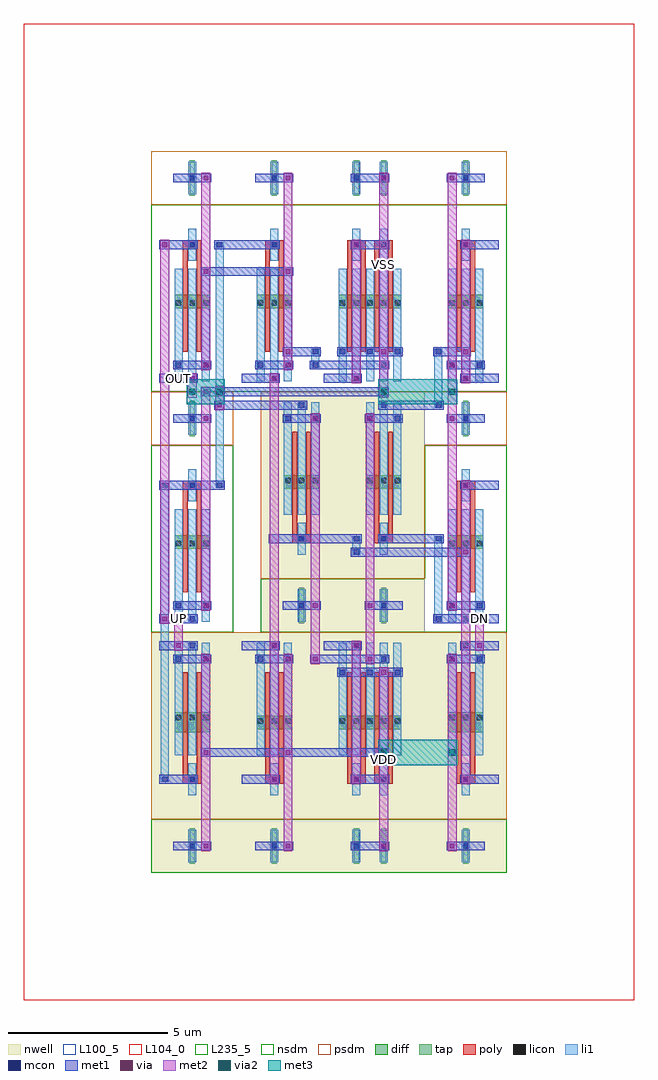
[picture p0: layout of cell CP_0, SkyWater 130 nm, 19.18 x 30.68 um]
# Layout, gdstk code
from math import pi, radians
import gdstk
lib = gdstk.Library(unit=1e-6, precision=1e-09)
def R(c, l, rs):  # rectangles x0, y0, x1, y1
    for r in rs: c.add(gdstk.rectangle(r[:2], r[2:], *l))
def A(c, l, x, y, w, h, nx, ny, dx, dy):  # array of equal rectangles
    R(c, l, [(x+i*dx, y+j*dy, x+i*dx+w, y+j*dy+h) for i in range(nx) for j in range(ny)])
def P(c, l, *ps):  # polygons
    for p in ps: c.add(gdstk.Polygon(p, *l))
nwell = (64, 20)
diff = (65, 20)
tap = (65, 44)
poly = (66, 20)
licon = (66, 44)
li1 = (67, 20)
mcon = (67, 44)
met1 = (68, 20)
via = (68, 44)
met2 = (69, 20)
via2 = (69, 44)
met3 = (70, 20)
nsdm = (93, 44)
psdm = (94, 20)
L100_5 = (100, 5)
L104_0 = (104, 0)
L235_5 = (235, 5)

scm_nmos_16357927_x1_y1_ = lib.new_cell('SCM_NMOS_16357927_X1_Y1_1670320497')
R(scm_nmos_16357927_x1_y1_, diff, [(0.735,2.625,2.705,3.045)])
R(scm_nmos_16357927_x1_y1_, tap, [(1.205,6.16,1.375,7.28), (2.065,6.16,2.235,7.28)])
A(scm_nmos_16357927_x1_y1_, poly, 1, 1.26, 0.15, 3.36, 4, 1, 0.43, 0)
R(scm_nmos_16357927_x1_y1_, poly, [(1,4.485,1.58,4.755), (1.86,4.485,2.44,4.755)])
A(scm_nmos_16357927_x1_y1_, licon, 0.775, 2.705, 0.17, 0.17, 3, 1, 0.43, 0)
A(scm_nmos_16357927_x1_y1_, licon, 1.635, 2.705, 0.17, 0.17, 3, 1, 0.43, 0)
R(scm_nmos_16357927_x1_y1_, licon, [(1.205,4.535,1.375,4.705), (2.065,4.535,2.235,4.705), (1.205,6.635,1.375,6.805), (2.065,6.635,2.235,6.805)])
A(scm_nmos_16357927_x1_y1_, li1, 0.735, 0.335, 0.25, 3.53, 5, 1, 0.43, 0)
R(scm_nmos_16357927_x1_y1_, li1, [(1.165,4.115,1.415,5.125), (2.025,4.115,2.275,5.125), (1.165,6.215,1.415,7.225), (2.025,6.215,2.275,7.225)])
A(scm_nmos_16357927_x1_y1_, mcon, 0.775, 1.175, 0.17, 0.17, 3, 1, 0.86, 0)
R(scm_nmos_16357927_x1_y1_, mcon, [(1.205,0.335,1.375,0.505), (2.065,0.755,2.235,0.925), (1.205,4.535,1.375,4.705), (2.065,4.535,2.235,4.705), (1.205,6.635,1.375,6.805), (2.065,6.635,2.235,6.805)])
R(scm_nmos_16357927_x1_y1_, met1, [(0.26,0.28,1.46,0.56), (1.12,0.7,2.32,0.98), (0.69,1.12,2.75,1.4), (1.12,4.48,2.32,4.76), (1.12,6.58,2.32,6.86)])
R(scm_nmos_16357927_x1_y1_, via, [(1.215,0.345,1.365,0.495), (2.075,1.185,2.225,1.335), (1.215,4.545,1.365,4.695), (2.075,6.645,2.225,6.795)])
R(scm_nmos_16357927_x1_y1_, met2, [(1.15,0.26,1.43,4.78), (2.01,1.1,2.29,6.88)])
R(scm_nmos_16357927_x1_y1_, nsdm, [(0,0,3.44,5.88)])
R(scm_nmos_16357927_x1_y1_, psdm, [(0,5.88,3.44,7.56)])
R(scm_nmos_16357927_x1_y1_, L100_5, [(0,0,3.44,7.56)])

scm_pmos_15963850_x1_y1_ = lib.new_cell('SCM_PMOS_15963850_X1_Y1_1670320498')
R(scm_pmos_15963850_x1_y1_, nwell, [(0,0,3.44,7.56)])
R(scm_pmos_15963850_x1_y1_, diff, [(0.735,2.625,2.705,3.045)])
R(scm_pmos_15963850_x1_y1_, tap, [(1.205,6.16,1.375,7.28), (2.065,6.16,2.235,7.28)])
A(scm_pmos_15963850_x1_y1_, poly, 1, 1.26, 0.15, 3.36, 4, 1, 0.43, 0)
R(scm_pmos_15963850_x1_y1_, poly, [(1,4.485,1.58,4.755), (1.86,4.485,2.44,4.755)])
A(scm_pmos_15963850_x1_y1_, licon, 0.775, 2.705, 0.17, 0.17, 3, 1, 0.43, 0)
A(scm_pmos_15963850_x1_y1_, licon, 1.635, 2.705, 0.17, 0.17, 3, 1, 0.43, 0)
R(scm_pmos_15963850_x1_y1_, licon, [(1.205,4.535,1.375,4.705), (2.065,4.535,2.235,4.705), (1.205,6.635,1.375,6.805), (2.065,6.635,2.235,6.805)])
A(scm_pmos_15963850_x1_y1_, li1, 0.735, 0.335, 0.25, 3.53, 5, 1, 0.43, 0)
R(scm_pmos_15963850_x1_y1_, li1, [(1.165,4.115,1.415,5.125), (2.025,4.115,2.275,5.125), (1.165,6.215,1.415,7.225), (2.025,6.215,2.275,7.225)])
A(scm_pmos_15963850_x1_y1_, mcon, 0.775, 1.175, 0.17, 0.17, 3, 1, 0.86, 0)
R(scm_pmos_15963850_x1_y1_, mcon, [(1.205,0.335,1.375,0.505), (2.065,0.755,2.235,0.925), (1.205,4.535,1.375,4.705), (2.065,4.535,2.235,4.705), (1.205,6.635,1.375,6.805), (2.065,6.635,2.235,6.805)])
R(scm_pmos_15963850_x1_y1_, met1, [(0.26,0.28,1.46,0.56), (1.12,0.7,2.32,0.98), (0.69,1.12,2.75,1.4), (1.12,4.48,2.32,4.76), (1.12,6.58,2.32,6.86)])
R(scm_pmos_15963850_x1_y1_, via, [(1.215,0.345,1.365,0.495), (2.075,1.185,2.225,1.335), (1.215,4.545,1.365,4.695), (2.075,6.645,2.225,6.795)])
R(scm_pmos_15963850_x1_y1_, met2, [(1.15,0.26,1.43,4.78), (2.01,1.1,2.29,6.88)])
R(scm_pmos_15963850_x1_y1_, nsdm, [(0,5.88,3.44,7.56)])
R(scm_pmos_15963850_x1_y1_, psdm, [(0,0,3.44,5.88)])
R(scm_pmos_15963850_x1_y1_, L100_5, [(0,0,3.44,7.56)])

nmos_s_96839798_x1_y1_16 = lib.new_cell('NMOS_S_96839798_X1_Y1_1670320484_1670320489')
R(nmos_s_96839798_x1_y1_16, diff, [(0.735,2.625,1.845,3.045)])
R(nmos_s_96839798_x1_y1_16, tap, [(1.205,6.16,1.375,7.28)])
R(nmos_s_96839798_x1_y1_16, poly, [(1,1.26,1.15,4.62), (1.43,1.26,1.58,4.62), (1,4.485,1.58,4.755)])
A(nmos_s_96839798_x1_y1_16, licon, 0.775, 2.705, 0.17, 0.17, 3, 1, 0.43, 0)
R(nmos_s_96839798_x1_y1_16, licon, [(1.205,4.535,1.375,4.705), (1.205,6.635,1.375,6.805)])
A(nmos_s_96839798_x1_y1_16, li1, 0.735, 0.335, 0.25, 3.53, 3, 1, 0.43, 0)
R(nmos_s_96839798_x1_y1_16, li1, [(1.165,4.115,1.415,5.125), (1.165,6.215,1.415,7.225)])
R(nmos_s_96839798_x1_y1_16, mcon, [(1.205,0.335,1.375,0.505), (0.775,0.755,0.945,0.925), (1.635,0.755,1.805,0.925), (1.205,4.535,1.375,4.705), (1.205,6.635,1.375,6.805)])
R(nmos_s_96839798_x1_y1_16, met1, [(0.26,0.28,1.46,0.56), (0.69,0.7,1.89,0.98), (0.26,4.48,1.46,4.76), (0.69,6.58,1.89,6.86)])
R(nmos_s_96839798_x1_y1_16, via, [(1.645,0.765,1.795,0.915), (1.645,6.645,1.795,6.795)])
R(nmos_s_96839798_x1_y1_16, met2, [(1.58,0.68,1.86,6.88)])
R(nmos_s_96839798_x1_y1_16, nsdm, [(0,0,2.58,5.88)])
R(nmos_s_96839798_x1_y1_16, psdm, [(0,5.88,2.58,7.56)])
R(nmos_s_96839798_x1_y1_16, L100_5, [(0,0,2.58,7.56)])

pmos_s_93230695_x1_y1_16 = lib.new_cell('PMOS_S_93230695_X1_Y1_1670320485_1670320489')
R(pmos_s_93230695_x1_y1_16, nwell, [(0,0,2.58,7.56)])
R(pmos_s_93230695_x1_y1_16, diff, [(0.735,2.52,1.845,3.15)])
R(pmos_s_93230695_x1_y1_16, tap, [(1.205,6.16,1.375,7.28)])
R(pmos_s_93230695_x1_y1_16, poly, [(1,1.26,1.15,4.62), (1.43,1.26,1.58,4.62), (1,4.485,1.58,4.755)])
A(pmos_s_93230695_x1_y1_16, licon, 0.775, 2.6, 0.17, 0.17, 3, 1, 0.43, 0)
R(pmos_s_93230695_x1_y1_16, licon, [(1.205,4.535,1.375,4.705), (1.205,6.635,1.375,6.805)])
A(pmos_s_93230695_x1_y1_16, li1, 0.735, 0.335, 0.25, 3.53, 3, 1, 0.43, 0)
R(pmos_s_93230695_x1_y1_16, li1, [(1.165,4.115,1.415,5.125), (1.165,6.215,1.415,7.225)])
R(pmos_s_93230695_x1_y1_16, mcon, [(1.205,0.335,1.375,0.505), (0.775,0.755,0.945,0.925), (1.635,0.755,1.805,0.925), (1.205,4.535,1.375,4.705), (1.205,6.635,1.375,6.805)])
R(pmos_s_93230695_x1_y1_16, met1, [(0.26,0.28,1.46,0.56), (0.69,0.7,1.89,0.98), (0.26,4.48,1.46,4.76), (0.69,6.58,1.89,6.86)])
R(pmos_s_93230695_x1_y1_16, via, [(1.645,0.765,1.795,0.915), (1.645,6.645,1.795,6.795)])
R(pmos_s_93230695_x1_y1_16, met2, [(1.58,0.68,1.86,6.88)])
R(pmos_s_93230695_x1_y1_16, nsdm, [(0,5.88,2.58,7.56)])
R(pmos_s_93230695_x1_y1_16, psdm, [(0,0,2.58,5.88)])
R(pmos_s_93230695_x1_y1_16, L100_5, [(0,0,2.58,7.56)])

inv_92586643_0_0_1670320 = lib.new_cell('INV_92586643_0_0_1670320489')
R(inv_92586643_0_0_1670320, li1, [(2.025,2.855,2.275,3.025), (2.025,2.855,2.275,3.025), (2.025,2.94,2.275,12.18), (2.025,12.095,2.275,12.265), (2.025,12.095,2.275,12.265)])
R(inv_92586643_0_0_1670320, mcon, [(2.065,2.855,2.235,3.025), (2.065,2.855,2.235,3.025), (2.065,12.095,2.235,12.265), (2.065,12.095,2.235,12.265)])
R(inv_92586643_0_0_1670320, met1, [(1.98,2.8,2.32,3.08), (1.98,2.8,2.32,3.08), (1.56,7,1.88,7.28), (1.56,7,1.88,7.28), (1.56,7.84,1.88,8.12), (1.56,7.84,1.88,8.12), (1.98,12.04,2.32,12.32), (1.98,12.04,2.32,12.32)])
P(inv_92586643_0_0_1670320, met1, [(0,0),(0,0),(0,0),(0,0)],
  [(0,0),(0,0),(0,0),(0,0)],
  [(0,0),(0,0),(0,0),(0,0)],
  [(0,0),(0,0),(0,0),(0,0)])
R(inv_92586643_0_0_1670320, via, [(1.645,7.065,1.795,7.215), (1.645,7.065,1.795,7.215), (1.645,7.905,1.795,8.055), (1.645,7.905,1.795,8.055)])
R(inv_92586643_0_0_1670320, met2, [(1.58,6.98,1.86,7.3), (1.58,6.98,1.86,7.3), (1.58,7.14,1.86,7.98), (1.58,7.82,1.86,8.14), (1.58,7.82,1.86,8.14)])
P(inv_92586643_0_0_1670320, met2, [(0,0),(0,0),(0,0),(0,0)],
  [(0,0),(0,0),(0,0),(0,0)])
R(inv_92586643_0_0_1670320, L235_5, [(0,0,2.58,15.12)])
inv_92586643_0_0_1670320.add(gdstk.Reference(nmos_s_96839798_x1_y1_16, (2.58,7.56), rotation=pi))
inv_92586643_0_0_1670320.add(gdstk.Reference(pmos_s_93230695_x1_y1_16, (2.58,7.56), rotation=pi, x_reflection=True))

c_nmos_s_96839798_x1_y1_16 = lib.new_cell('NMOS_S_96839798_X1_Y1_1670320484_1670320490')
R(c_nmos_s_96839798_x1_y1_16, diff, [(0.735,2.625,1.845,3.045)])
R(c_nmos_s_96839798_x1_y1_16, tap, [(1.205,6.16,1.375,7.28)])
R(c_nmos_s_96839798_x1_y1_16, poly, [(1,1.26,1.15,4.62), (1.43,1.26,1.58,4.62), (1,4.485,1.58,4.755)])
A(c_nmos_s_96839798_x1_y1_16, licon, 0.775, 2.705, 0.17, 0.17, 3, 1, 0.43, 0)
R(c_nmos_s_96839798_x1_y1_16, licon, [(1.205,4.535,1.375,4.705), (1.205,6.635,1.375,6.805)])
A(c_nmos_s_96839798_x1_y1_16, li1, 0.735, 0.335, 0.25, 3.53, 3, 1, 0.43, 0)
R(c_nmos_s_96839798_x1_y1_16, li1, [(1.165,4.115,1.415,5.125), (1.165,6.215,1.415,7.225)])
R(c_nmos_s_96839798_x1_y1_16, mcon, [(1.205,0.335,1.375,0.505), (0.775,0.755,0.945,0.925), (1.635,0.755,1.805,0.925), (1.205,4.535,1.375,4.705), (1.205,6.635,1.375,6.805)])
R(c_nmos_s_96839798_x1_y1_16, met1, [(0.26,0.28,1.46,0.56), (0.69,0.7,1.89,0.98), (0.26,4.48,1.46,4.76), (0.69,6.58,1.89,6.86)])
R(c_nmos_s_96839798_x1_y1_16, via, [(1.645,0.765,1.795,0.915), (1.645,6.645,1.795,6.795)])
R(c_nmos_s_96839798_x1_y1_16, met2, [(1.58,0.68,1.86,6.88)])
R(c_nmos_s_96839798_x1_y1_16, nsdm, [(0,0,2.58,5.88)])
R(c_nmos_s_96839798_x1_y1_16, psdm, [(0,5.88,2.58,7.56)])
R(c_nmos_s_96839798_x1_y1_16, L100_5, [(0,0,2.58,7.56)])

c_pmos_s_93230695_x1_y1_16 = lib.new_cell('PMOS_S_93230695_X1_Y1_1670320485_1670320490')
R(c_pmos_s_93230695_x1_y1_16, nwell, [(0,0,2.58,7.56)])
R(c_pmos_s_93230695_x1_y1_16, diff, [(0.735,2.52,1.845,3.15)])
R(c_pmos_s_93230695_x1_y1_16, tap, [(1.205,6.16,1.375,7.28)])
R(c_pmos_s_93230695_x1_y1_16, poly, [(1,1.26,1.15,4.62), (1.43,1.26,1.58,4.62), (1,4.485,1.58,4.755)])
A(c_pmos_s_93230695_x1_y1_16, licon, 0.775, 2.6, 0.17, 0.17, 3, 1, 0.43, 0)
R(c_pmos_s_93230695_x1_y1_16, licon, [(1.205,4.535,1.375,4.705), (1.205,6.635,1.375,6.805)])
A(c_pmos_s_93230695_x1_y1_16, li1, 0.735, 0.335, 0.25, 3.53, 3, 1, 0.43, 0)
R(c_pmos_s_93230695_x1_y1_16, li1, [(1.165,4.115,1.415,5.125), (1.165,6.215,1.415,7.225)])
R(c_pmos_s_93230695_x1_y1_16, mcon, [(1.205,0.335,1.375,0.505), (0.775,0.755,0.945,0.925), (1.635,0.755,1.805,0.925), (1.205,4.535,1.375,4.705), (1.205,6.635,1.375,6.805)])
R(c_pmos_s_93230695_x1_y1_16, met1, [(0.26,0.28,1.46,0.56), (0.69,0.7,1.89,0.98), (0.26,4.48,1.46,4.76), (0.69,6.58,1.89,6.86)])
R(c_pmos_s_93230695_x1_y1_16, via, [(1.645,0.765,1.795,0.915), (1.645,6.645,1.795,6.795)])
R(c_pmos_s_93230695_x1_y1_16, met2, [(1.58,0.68,1.86,6.88)])
R(c_pmos_s_93230695_x1_y1_16, nsdm, [(0,5.88,2.58,7.56)])
R(c_pmos_s_93230695_x1_y1_16, psdm, [(0,0,2.58,5.88)])
R(c_pmos_s_93230695_x1_y1_16, L100_5, [(0,0,2.58,7.56)])

inv_92586643_1_0_1670320 = lib.new_cell('INV_92586643_1_0_1670320490')
R(inv_92586643_1_0_1670320, met1, [(1.13,2.8,1.45,3.08), (1.13,2.8,1.45,3.08), (1.56,7,1.88,7.28), (1.56,7,1.88,7.28), (1.56,7.84,1.88,8.12), (1.56,7.84,1.88,8.12), (1.13,12.04,1.45,12.32), (1.13,12.04,1.45,12.32)])
P(inv_92586643_1_0_1670320, met1, [(0,0),(0,0),(0,0),(0,0)],
  [(0,0),(0,0),(0,0),(0,0)],
  [(0,0),(0,0),(0,0),(0,0)],
  [(0,0),(0,0),(0,0),(0,0)])
R(inv_92586643_1_0_1670320, via, [(1.215,2.865,1.365,3.015), (1.215,2.865,1.365,3.015), (1.645,7.065,1.795,7.215), (1.645,7.065,1.795,7.215), (1.645,7.905,1.795,8.055), (1.645,7.905,1.795,8.055), (1.215,12.105,1.365,12.255), (1.215,12.105,1.365,12.255)])
R(inv_92586643_1_0_1670320, met2, [(1.15,2.78,1.43,3.1), (1.15,2.78,1.43,3.1), (1.15,2.94,1.43,12.18), (1.58,6.98,1.86,7.3), (1.58,6.98,1.86,7.3), (1.58,7.14,1.86,7.98), (1.58,7.82,1.86,8.14), (1.58,7.82,1.86,8.14), (1.15,12.02,1.43,12.34), (1.15,12.02,1.43,12.34)])
P(inv_92586643_1_0_1670320, met2, [(0,0),(0,0),(0,0),(0,0)],
  [(0,0),(0,0),(0,0),(0,0)])
R(inv_92586643_1_0_1670320, L235_5, [(0,0,2.58,15.12)])
inv_92586643_1_0_1670320.add(gdstk.Reference(c_nmos_s_96839798_x1_y1_16, (2.58,7.56), rotation=pi))
inv_92586643_1_0_1670320.add(gdstk.Reference(c_pmos_s_93230695_x1_y1_16, (2.58,7.56), rotation=pi, x_reflection=True))

dcl_nmos_s_62101695_x1_y = lib.new_cell('DCL_NMOS_S_62101695_X1_Y1_1670320491')
R(dcl_nmos_s_62101695_x1_y, diff, [(0.735,2.625,1.845,3.045)])
R(dcl_nmos_s_62101695_x1_y, tap, [(1.205,6.16,1.375,7.28)])
R(dcl_nmos_s_62101695_x1_y, poly, [(1,1.26,1.15,4.62), (1.43,1.26,1.58,4.62), (1,4.485,1.58,4.755)])
A(dcl_nmos_s_62101695_x1_y, licon, 0.775, 2.705, 0.17, 0.17, 3, 1, 0.43, 0)
R(dcl_nmos_s_62101695_x1_y, licon, [(1.205,4.535,1.375,4.705), (1.205,6.635,1.375,6.805)])
A(dcl_nmos_s_62101695_x1_y, li1, 0.735, 0.335, 0.25, 3.53, 3, 1, 0.43, 0)
R(dcl_nmos_s_62101695_x1_y, li1, [(1.165,4.115,1.415,5.125), (1.165,6.215,1.415,7.225)])
R(dcl_nmos_s_62101695_x1_y, mcon, [(1.205,0.335,1.375,0.505), (0.775,0.755,0.945,0.925), (1.635,0.755,1.805,0.925), (1.205,4.535,1.375,4.705), (1.205,6.635,1.375,6.805)])
R(dcl_nmos_s_62101695_x1_y, met1, [(0.26,0.28,1.46,0.56), (0.69,0.7,1.89,0.98), (0.26,4.48,1.46,4.76), (0.69,6.58,1.89,6.86)])
R(dcl_nmos_s_62101695_x1_y, via, [(1.215,0.345,1.365,0.495), (1.645,0.765,1.795,0.915), (1.215,4.545,1.365,4.695), (1.645,6.645,1.795,6.795)])
R(dcl_nmos_s_62101695_x1_y, met2, [(1.15,0.26,1.43,4.78), (1.58,0.68,1.86,6.88)])
R(dcl_nmos_s_62101695_x1_y, nsdm, [(0,0,2.58,5.88)])
R(dcl_nmos_s_62101695_x1_y, psdm, [(0,5.88,2.58,7.56)])
R(dcl_nmos_s_62101695_x1_y, L100_5, [(0,0,2.58,7.56)])

dcl_pmos_s_57934405_x1_y = lib.new_cell('DCL_PMOS_S_57934405_X1_Y1_1670320492')
R(dcl_pmos_s_57934405_x1_y, nwell, [(0,0,2.58,7.56)])
R(dcl_pmos_s_57934405_x1_y, diff, [(0.735,2.625,1.845,3.045)])
R(dcl_pmos_s_57934405_x1_y, tap, [(1.205,6.16,1.375,7.28)])
R(dcl_pmos_s_57934405_x1_y, poly, [(1,1.26,1.15,4.62), (1.43,1.26,1.58,4.62), (1,4.485,1.58,4.755)])
A(dcl_pmos_s_57934405_x1_y, licon, 0.775, 2.705, 0.17, 0.17, 3, 1, 0.43, 0)
R(dcl_pmos_s_57934405_x1_y, licon, [(1.205,4.535,1.375,4.705), (1.205,6.635,1.375,6.805)])
A(dcl_pmos_s_57934405_x1_y, li1, 0.735, 0.335, 0.25, 3.53, 3, 1, 0.43, 0)
R(dcl_pmos_s_57934405_x1_y, li1, [(1.165,4.115,1.415,5.125), (1.165,6.215,1.415,7.225)])
R(dcl_pmos_s_57934405_x1_y, mcon, [(1.205,0.335,1.375,0.505), (0.775,0.755,0.945,0.925), (1.635,0.755,1.805,0.925), (1.205,4.535,1.375,4.705), (1.205,6.635,1.375,6.805)])
R(dcl_pmos_s_57934405_x1_y, met1, [(0.26,0.28,1.46,0.56), (0.69,0.7,1.89,0.98), (0.26,4.48,1.46,4.76), (0.69,6.58,1.89,6.86)])
R(dcl_pmos_s_57934405_x1_y, via, [(1.215,0.345,1.365,0.495), (1.645,0.765,1.795,0.915), (1.215,4.545,1.365,4.695), (1.645,6.645,1.795,6.795)])
R(dcl_pmos_s_57934405_x1_y, met2, [(1.15,0.26,1.43,4.78), (1.58,0.68,1.86,6.88)])
R(dcl_pmos_s_57934405_x1_y, nsdm, [(0,5.88,2.58,7.56)])
R(dcl_pmos_s_57934405_x1_y, psdm, [(0,0,2.58,5.88)])
R(dcl_pmos_s_57934405_x1_y, L100_5, [(0,0,2.58,7.56)])

nmos_s_58782418_x1_y1_16 = lib.new_cell('NMOS_S_58782418_X1_Y1_1670320493')
R(nmos_s_58782418_x1_y1_16, diff, [(0.735,2.625,1.845,3.045)])
R(nmos_s_58782418_x1_y1_16, tap, [(1.205,6.16,1.375,7.28)])
R(nmos_s_58782418_x1_y1_16, poly, [(1,1.26,1.15,4.62), (1.43,1.26,1.58,4.62), (1,4.485,1.58,4.755)])
A(nmos_s_58782418_x1_y1_16, licon, 0.775, 2.705, 0.17, 0.17, 3, 1, 0.43, 0)
R(nmos_s_58782418_x1_y1_16, licon, [(1.205,4.535,1.375,4.705), (1.205,6.635,1.375,6.805)])
A(nmos_s_58782418_x1_y1_16, li1, 0.735, 0.335, 0.25, 3.53, 3, 1, 0.43, 0)
R(nmos_s_58782418_x1_y1_16, li1, [(1.165,4.115,1.415,5.125), (1.165,6.215,1.415,7.225)])
R(nmos_s_58782418_x1_y1_16, mcon, [(1.205,0.335,1.375,0.505), (0.775,0.755,0.945,0.925), (1.635,0.755,1.805,0.925), (1.205,4.535,1.375,4.705), (1.205,6.635,1.375,6.805)])
R(nmos_s_58782418_x1_y1_16, met1, [(0.26,0.28,1.46,0.56), (0.69,0.7,1.89,0.98), (0.26,4.48,1.46,4.76), (0.69,6.58,1.89,6.86)])
R(nmos_s_58782418_x1_y1_16, via, [(1.645,0.765,1.795,0.915), (1.645,6.645,1.795,6.795)])
R(nmos_s_58782418_x1_y1_16, met2, [(1.58,0.68,1.86,6.88)])
R(nmos_s_58782418_x1_y1_16, nsdm, [(0,0,2.58,5.88)])
R(nmos_s_58782418_x1_y1_16, psdm, [(0,5.88,2.58,7.56)])
R(nmos_s_58782418_x1_y1_16, L100_5, [(0,0,2.58,7.56)])

c_nmos_s_96839798_x1_y1_16_ = lib.new_cell('NMOS_S_96839798_X1_Y1_1670320494')
R(c_nmos_s_96839798_x1_y1_16_, diff, [(0.735,2.625,1.845,3.045)])
R(c_nmos_s_96839798_x1_y1_16_, tap, [(1.205,6.16,1.375,7.28)])
R(c_nmos_s_96839798_x1_y1_16_, poly, [(1,1.26,1.15,4.62), (1.43,1.26,1.58,4.62), (1,4.485,1.58,4.755)])
A(c_nmos_s_96839798_x1_y1_16_, licon, 0.775, 2.705, 0.17, 0.17, 3, 1, 0.43, 0)
R(c_nmos_s_96839798_x1_y1_16_, licon, [(1.205,4.535,1.375,4.705), (1.205,6.635,1.375,6.805)])
A(c_nmos_s_96839798_x1_y1_16_, li1, 0.735, 0.335, 0.25, 3.53, 3, 1, 0.43, 0)
R(c_nmos_s_96839798_x1_y1_16_, li1, [(1.165,4.115,1.415,5.125), (1.165,6.215,1.415,7.225)])
R(c_nmos_s_96839798_x1_y1_16_, mcon, [(1.205,0.335,1.375,0.505), (0.775,0.755,0.945,0.925), (1.635,0.755,1.805,0.925), (1.205,4.535,1.375,4.705), (1.205,6.635,1.375,6.805)])
R(c_nmos_s_96839798_x1_y1_16_, met1, [(0.26,0.28,1.46,0.56), (0.69,0.7,1.89,0.98), (0.26,4.48,1.46,4.76), (0.69,6.58,1.89,6.86)])
R(c_nmos_s_96839798_x1_y1_16_, via, [(1.645,0.765,1.795,0.915), (1.645,6.645,1.795,6.795)])
R(c_nmos_s_96839798_x1_y1_16_, met2, [(1.58,0.68,1.86,6.88)])
R(c_nmos_s_96839798_x1_y1_16_, nsdm, [(0,0,2.58,5.88)])
R(c_nmos_s_96839798_x1_y1_16_, psdm, [(0,5.88,2.58,7.56)])
R(c_nmos_s_96839798_x1_y1_16_, L100_5, [(0,0,2.58,7.56)])

pmos_s_48783884_x1_y1_16 = lib.new_cell('PMOS_S_48783884_X1_Y1_1670320495')
R(pmos_s_48783884_x1_y1_16, nwell, [(0,0,2.58,7.56)])
R(pmos_s_48783884_x1_y1_16, diff, [(0.735,2.625,1.845,3.045)])
R(pmos_s_48783884_x1_y1_16, tap, [(1.205,6.16,1.375,7.28)])
R(pmos_s_48783884_x1_y1_16, poly, [(1,1.26,1.15,4.62), (1.43,1.26,1.58,4.62), (1,4.485,1.58,4.755)])
A(pmos_s_48783884_x1_y1_16, licon, 0.775, 2.705, 0.17, 0.17, 3, 1, 0.43, 0)
R(pmos_s_48783884_x1_y1_16, licon, [(1.205,4.535,1.375,4.705), (1.205,6.635,1.375,6.805)])
A(pmos_s_48783884_x1_y1_16, li1, 0.735, 0.335, 0.25, 3.53, 3, 1, 0.43, 0)
R(pmos_s_48783884_x1_y1_16, li1, [(1.165,4.115,1.415,5.125), (1.165,6.215,1.415,7.225)])
R(pmos_s_48783884_x1_y1_16, mcon, [(1.205,0.335,1.375,0.505), (0.775,0.755,0.945,0.925), (1.635,0.755,1.805,0.925), (1.205,4.535,1.375,4.705), (1.205,6.635,1.375,6.805)])
R(pmos_s_48783884_x1_y1_16, met1, [(0.26,0.28,1.46,0.56), (0.69,0.7,1.89,0.98), (0.26,4.48,1.46,4.76), (0.69,6.58,1.89,6.86)])
R(pmos_s_48783884_x1_y1_16, via, [(1.645,0.765,1.795,0.915), (1.645,6.645,1.795,6.795)])
R(pmos_s_48783884_x1_y1_16, met2, [(1.58,0.68,1.86,6.88)])
R(pmos_s_48783884_x1_y1_16, nsdm, [(0,5.88,2.58,7.56)])
R(pmos_s_48783884_x1_y1_16, psdm, [(0,0,2.58,5.88)])
R(pmos_s_48783884_x1_y1_16, L100_5, [(0,0,2.58,7.56)])

pmos_s_63670781_x1_y1_16 = lib.new_cell('PMOS_S_63670781_X1_Y1_1670320496')
R(pmos_s_63670781_x1_y1_16, nwell, [(0,0,2.58,7.56)])
R(pmos_s_63670781_x1_y1_16, diff, [(0.735,2.625,1.845,3.045)])
R(pmos_s_63670781_x1_y1_16, tap, [(1.205,6.16,1.375,7.28)])
R(pmos_s_63670781_x1_y1_16, poly, [(1,1.26,1.15,4.62), (1.43,1.26,1.58,4.62), (1,4.485,1.58,4.755)])
A(pmos_s_63670781_x1_y1_16, licon, 0.775, 2.705, 0.17, 0.17, 3, 1, 0.43, 0)
R(pmos_s_63670781_x1_y1_16, licon, [(1.205,4.535,1.375,4.705), (1.205,6.635,1.375,6.805)])
A(pmos_s_63670781_x1_y1_16, li1, 0.735, 0.335, 0.25, 3.53, 3, 1, 0.43, 0)
R(pmos_s_63670781_x1_y1_16, li1, [(1.165,4.115,1.415,5.125), (1.165,6.215,1.415,7.225)])
R(pmos_s_63670781_x1_y1_16, mcon, [(1.205,0.335,1.375,0.505), (0.775,0.755,0.945,0.925), (1.635,0.755,1.805,0.925), (1.205,4.535,1.375,4.705), (1.205,6.635,1.375,6.805)])
R(pmos_s_63670781_x1_y1_16, met1, [(0.26,0.28,1.46,0.56), (0.69,0.7,1.89,0.98), (0.26,4.48,1.46,4.76), (0.69,6.58,1.89,6.86)])
R(pmos_s_63670781_x1_y1_16, via, [(1.645,0.765,1.795,0.915), (1.645,6.645,1.795,6.795)])
R(pmos_s_63670781_x1_y1_16, met2, [(1.58,0.68,1.86,6.88)])
R(pmos_s_63670781_x1_y1_16, nsdm, [(0,5.88,2.58,7.56)])
R(pmos_s_63670781_x1_y1_16, psdm, [(0,0,2.58,5.88)])
R(pmos_s_63670781_x1_y1_16, L100_5, [(0,0,2.58,7.56)])

cp_0 = lib.new_cell('CP_0')
R(cp_0, li1, [(8.905,7.895,9.155,8.065), (8.905,7.895,9.155,8.065), (8.905,7.98,9.155,10.5), (6.325,9.995,6.575,10.165), (6.325,9.995,6.575,10.165), (6.325,10.08,6.575,10.5), (6.325,10.415,6.575,10.585), (6.325,10.415,6.575,10.585), (8.905,10.415,9.155,10.585), (8.905,10.415,9.155,10.585), (2.025,12.095,2.275,12.265), (2.025,12.095,2.275,12.265), (2.025,12.18,2.275,19.74), (8.905,14.615,9.155,14.785), (8.905,14.615,9.155,14.785), (8.905,14.7,9.155,16.38), (5.035,15.875,5.285,16.045), (5.035,15.875,5.285,16.045), (5.035,15.875,5.285,16.045), (5.035,15.875,5.285,16.045), (5.035,15.96,5.285,16.38), (5.035,16.295,5.285,16.465), (5.035,16.295,5.285,16.465), (5.035,16.295,5.285,16.465), (5.035,16.295,5.285,16.465), (8.905,16.295,9.155,16.465), (8.905,16.295,9.155,16.465), (2.025,19.655,2.275,19.825), (2.025,19.655,2.275,19.825)])
P(cp_0, li1, [(0,0),(0,0),(0,0),(0,0)])
R(cp_0, mcon, [(8.945,7.895,9.115,8.065), (8.945,7.895,9.115,8.065), (6.365,9.995,6.535,10.165), (6.365,9.995,6.535,10.165), (6.365,10.415,6.535,10.585), (6.365,10.415,6.535,10.585), (8.945,10.415,9.115,10.585), (8.945,10.415,9.115,10.585), (2.065,12.095,2.235,12.265), (2.065,12.095,2.235,12.265), (8.945,14.615,9.115,14.785), (8.945,14.615,9.115,14.785), (5.075,15.875,5.245,16.045), (5.075,15.875,5.245,16.045), (5.075,15.875,5.245,16.045), (5.075,15.875,5.245,16.045), (5.075,16.295,5.245,16.465), (5.075,16.295,5.245,16.465), (5.075,16.295,5.245,16.465), (5.075,16.295,5.245,16.465), (8.945,16.295,9.115,16.465), (8.945,16.295,9.115,16.465), (2.065,19.655,2.235,19.825), (2.065,19.655,2.235,19.825)])
R(cp_0, met1, [(1.56,3.64,1.88,3.92), (1.56,3.64,1.88,3.92), (1.56,3.64,1.88,3.92), (1.56,3.64,1.88,3.92), (1.56,3.64,1.88,3.92), (1.56,3.64,1.88,3.92), (1.72,3.64,7.31,3.92), (4.14,3.64,4.46,3.92), (4.14,3.64,4.46,3.92), (7.15,3.64,7.47,3.92), (7.15,3.64,7.47,3.92), (7.15,3.64,7.47,3.92), (7.15,3.64,7.47,3.92), (7.15,3.64,7.47,3.92), (7.15,3.64,7.47,3.92), (5,6.58,5.32,6.86), (5,6.58,5.32,6.86), (5,6.58,5.32,6.86), (5,6.58,5.32,6.86), (5.16,6.58,6.45,6.86), (6.72,6.58,7.04,6.86), (6.72,6.58,7.04,6.86), (0.27,7.84,0.59,8.12), (0.27,7.84,0.59,8.12), (8.86,7.84,9.2,8.12), (8.86,7.84,9.2,8.12), (9.03,7.84,9.89,8.12), (6.28,9.94,6.62,10.22), (6.28,9.94,6.62,10.22), (6.45,9.94,9.89,10.22), (9.73,9.94,10.05,10.22), (9.73,9.94,10.05,10.22), (4.73,10.36,6.45,10.64), (6.28,10.36,6.62,10.64), (6.28,10.36,6.62,10.64), (8.17,10.36,9.03,10.64), (8.86,10.36,9.2,10.64), (8.86,10.36,9.2,10.64), (1.29,12.04,2.15,12.32), (1.98,12.04,2.32,12.32), (1.98,12.04,2.32,12.32), (1.99,14.56,2.31,14.84), (1.99,14.56,2.31,14.84), (2.15,14.56,3.87,14.84), (8.17,14.56,9.03,14.84), (8.86,14.56,9.2,14.84), (8.86,14.56,9.2,14.84), (1.56,14.98,1.88,15.26), (1.56,14.98,1.88,15.26), (1.56,14.98,1.88,15.26), (1.56,14.98,1.88,15.26), (1.56,14.98,1.88,15.26), (1.56,14.98,1.88,15.26), (1.72,14.98,7.31,15.26), (7.15,14.98,7.47,15.26), (7.15,14.98,7.47,15.26), (7.15,14.98,7.47,15.26), (7.15,14.98,7.47,15.26), (7.15,14.98,7.47,15.26), (7.15,14.98,7.47,15.26), (1.13,15.4,1.45,15.68), (1.13,15.4,1.45,15.68), (3.71,15.4,4.03,15.68), (3.71,15.4,4.03,15.68), (4.99,15.82,5.33,16.1), (4.99,15.82,5.33,16.1), (4.99,15.82,5.33,16.1), (4.99,15.82,5.33,16.1), (5.16,15.82,6.45,16.1), (4.14,16.24,4.46,16.52), (4.14,16.24,4.46,16.52), (4.14,16.24,4.46,16.52), (4.14,16.24,4.46,16.52), (4.3,16.24,5.16,16.52), (4.99,16.24,5.33,16.52), (4.99,16.24,5.33,16.52), (4.99,16.24,5.33,16.52), (4.99,16.24,5.33,16.52), (8.86,16.24,9.2,16.52), (8.86,16.24,9.2,16.52), (9.03,16.24,9.89,16.52), (9.73,16.24,10.05,16.52), (9.73,16.24,10.05,16.52), (1.56,18.76,1.88,19.04), (1.56,18.76,1.88,19.04), (1.72,18.76,4.3,19.04), (4.14,18.76,4.46,19.04), (4.14,18.76,4.46,19.04), (0.27,19.6,0.59,19.88), (0.27,19.6,0.59,19.88), (1.98,19.6,2.32,19.88), (1.98,19.6,2.32,19.88), (2.15,19.6,3.01,19.88)])
P(cp_0, met1, [(0,0),(0,0),(0,0),(0,0)],
  [(0,0),(0,0),(0,0),(0,0)],
  [(0,0),(0,0),(0,0),(0,0)],
  [(0,0),(0,0),(0,0),(0,0)],
  [(0,0),(0,0),(0,0),(0,0)],
  [(0,0),(0,0),(0,0),(0,0)],
  [(0,0),(0,0),(0,0),(0,0)],
  [(0,0),(0,0),(0,0),(0,0)],
  [(0,0),(0,0),(0,0),(0,0)],
  [(0,0),(0,0),(0,0),(0,0)],
  [(0,0),(0,0),(0,0),(0,0)],
  [(0,0),(0,0),(0,0),(0,0)],
  [(0,0),(0,0),(0,0),(0,0)],
  [(0,0),(0,0),(0,0),(0,0)],
  [(0,0),(0,0),(0,0),(0,0)],
  [(0,0),(0,0),(0,0),(0,0)],
  [(0,0),(0,0),(0,0),(0,0)],
  [(0,0),(0,0),(0,0),(0,0)],
  [(0,0),(0,0),(0,0),(0,0)],
  [(0,0),(0,0),(0,0),(0,0)],
  [(0,0),(0,0),(0,0),(0,0)],
  [(0,0),(0,0),(0,0),(0,0)],
  [(0,0),(0,0),(0,0),(0,0)],
  [(0,0),(0,0),(0,0),(0,0)],
  [(0,0),(0,0),(0,0),(0,0)],
  [(0,0),(0,0),(0,0),(0,0)],
  [(0,0),(0,0),(0,0),(0,0)],
  [(0,0),(0,0),(0,0),(0,0)],
  [(0,0),(0,0),(0,0),(0,0)])
R(cp_0, via, [(1.645,3.705,1.795,3.855), (1.645,3.705,1.795,3.855), (1.645,3.705,1.795,3.855), (1.645,3.705,1.795,3.855), (1.645,3.705,1.795,3.855), (1.645,3.705,1.795,3.855), (4.225,3.705,4.375,3.855), (4.225,3.705,4.375,3.855), (7.235,3.705,7.385,3.855), (7.235,3.705,7.385,3.855), (7.235,3.705,7.385,3.855), (7.235,3.705,7.385,3.855), (7.235,3.705,7.385,3.855), (7.235,3.705,7.385,3.855), (5.085,6.645,5.235,6.795), (5.085,6.645,5.235,6.795), (5.085,6.645,5.235,6.795), (5.085,6.645,5.235,6.795), (6.805,6.645,6.955,6.795), (6.805,6.645,6.955,6.795), (0.355,7.905,0.505,8.055), (0.355,7.905,0.505,8.055), (9.815,10.005,9.965,10.155), (9.815,10.005,9.965,10.155), (2.075,14.625,2.225,14.775), (2.075,14.625,2.225,14.775), (1.645,15.045,1.795,15.195), (1.645,15.045,1.795,15.195), (1.645,15.045,1.795,15.195), (1.645,15.045,1.795,15.195), (1.645,15.045,1.795,15.195), (1.645,15.045,1.795,15.195), (7.235,15.045,7.385,15.195), (7.235,15.045,7.385,15.195), (7.235,15.045,7.385,15.195), (7.235,15.045,7.385,15.195), (7.235,15.045,7.385,15.195), (7.235,15.045,7.385,15.195), (1.215,15.465,1.365,15.615), (1.215,15.465,1.365,15.615), (3.795,15.465,3.945,15.615), (3.795,15.465,3.945,15.615), (4.225,16.305,4.375,16.455), (4.225,16.305,4.375,16.455), (4.225,16.305,4.375,16.455), (4.225,16.305,4.375,16.455), (9.815,16.305,9.965,16.455), (9.815,16.305,9.965,16.455), (1.645,18.825,1.795,18.975), (1.645,18.825,1.795,18.975), (4.225,18.825,4.375,18.975), (4.225,18.825,4.375,18.975), (0.355,19.665,0.505,19.815), (0.355,19.665,0.505,19.815)])
R(cp_0, met2, [(7.17,3.595,7.45,3.965), (7.17,3.595,7.45,3.965), (7.17,3.595,7.45,3.965), (7.17,3.595,7.45,3.965), (9.32,3.595,9.6,3.965), (9.32,3.595,9.6,3.965), (9.32,3.595,9.6,3.965), (9.32,3.595,9.6,3.965), (1.58,3.62,1.86,3.94), (1.58,3.62,1.86,3.94), (1.58,3.62,1.86,3.94), (1.58,3.62,1.86,3.94), (1.58,3.62,1.86,3.94), (1.58,3.62,1.86,3.94), (4.16,3.62,4.44,3.94), (4.16,3.62,4.44,3.94), (7.17,3.62,7.45,3.94), (7.17,3.62,7.45,3.94), (7.17,3.62,7.45,3.94), (7.17,3.62,7.45,3.94), (7.17,3.62,7.45,3.94), (7.17,3.62,7.45,3.94), (5.02,6.56,5.3,6.88), (5.02,6.56,5.3,6.88), (5.02,6.56,5.3,6.88), (5.02,6.56,5.3,6.88), (6.74,6.56,7.02,6.88), (6.74,6.56,7.02,6.88), (5.02,6.72,5.3,8.4), (6.74,6.72,7.02,8.4), (3.73,7.14,4.01,15.54), (0.29,7.82,0.57,8.14), (0.29,7.82,0.57,8.14), (0.29,7.98,0.57,19.74), (9.75,9.92,10.03,10.24), (9.75,9.92,10.03,10.24), (1.58,14.28,1.86,15.12), (9.32,14.28,9.6,15.12), (2.01,14.54,2.29,14.86), (2.01,14.54,2.29,14.86), (2.01,14.7,2.29,15.12), (1.15,14.935,1.43,15.305), (1.15,14.935,1.43,15.305), (2.01,14.935,2.29,15.305), (2.01,14.935,2.29,15.305), (7.17,14.935,7.45,15.305), (7.17,14.935,7.45,15.305), (7.17,14.935,7.45,15.305), (7.17,14.935,7.45,15.305), (9.32,14.935,9.6,15.305), (9.32,14.935,9.6,15.305), (9.32,14.935,9.6,15.305), (9.32,14.935,9.6,15.305), (1.58,14.96,1.86,15.28), (1.58,14.96,1.86,15.28), (1.58,14.96,1.86,15.28), (1.58,14.96,1.86,15.28), (1.58,14.96,1.86,15.28), (1.58,14.96,1.86,15.28), (7.17,14.96,7.45,15.28), (7.17,14.96,7.45,15.28), (7.17,14.96,7.45,15.28), (7.17,14.96,7.45,15.28), (7.17,14.96,7.45,15.28), (7.17,14.96,7.45,15.28), (1.15,15.12,1.43,15.54), (7.17,15.12,7.45,16.38), (9.32,15.12,9.6,15.96), (1.15,15.38,1.43,15.7), (1.15,15.38,1.43,15.7), (3.73,15.38,4.01,15.7), (3.73,15.38,4.01,15.7), (4.16,16.22,4.44,16.54), (4.16,16.22,4.44,16.54), (4.16,16.22,4.44,16.54), (4.16,16.22,4.44,16.54), (9.75,16.22,10.03,16.54), (9.75,16.22,10.03,16.54), (1.58,18.74,1.86,19.06), (1.58,18.74,1.86,19.06), (4.16,18.74,4.44,19.06), (4.16,18.74,4.44,19.06), (0.29,19.58,0.57,19.9), (0.29,19.58,0.57,19.9)])
P(cp_0, met2, [(0,0),(0,0),(0,0),(0,0)],
  [(0,0),(0,0),(0,0),(0,0)],
  [(0,0),(0,0),(0,0),(0,0)],
  [(0,0),(0,0),(0,0),(0,0)],
  [(0,0),(0,0),(0,0),(0,0)],
  [(0,0),(0,0),(0,0),(0,0)],
  [(0,0),(0,0),(0,0),(0,0)],
  [(0,0),(0,0),(0,0),(0,0)],
  [(0,0),(0,0),(0,0),(0,0)],
  [(0,0),(0,0),(0,0),(0,0)],
  [(0,0),(0,0),(0,0),(0,0)],
  [(0,0),(0,0),(0,0),(0,0)],
  [(0,0),(0,0),(0,0),(0,0)],
  [(0,0),(0,0),(0,0),(0,0)],
  [(0,0),(0,0),(0,0),(0,0)],
  [(0,0),(0,0),(0,0),(0,0)],
  [(0,0),(0,0),(0,0),(0,0)],
  [(0,0),(0,0),(0,0),(0,0)],
  [(0,0),(0,0),(0,0),(0,0)],
  [(0,0),(0,0),(0,0),(0,0)],
  [(0,0),(0,0),(0,0),(0,0)])
R(cp_0, via2, [(7.21,3.68,7.41,3.88), (7.21,3.68,7.41,3.88), (7.21,3.68,7.41,3.88), (7.21,3.68,7.41,3.88), (9.36,3.68,9.56,3.88), (9.36,3.68,9.56,3.88), (9.36,3.68,9.56,3.88), (9.36,3.68,9.56,3.88), (1.19,15.02,1.39,15.22), (1.19,15.02,1.39,15.22), (2.05,15.02,2.25,15.22), (2.05,15.02,2.25,15.22), (7.21,15.02,7.41,15.22), (7.21,15.02,7.41,15.22), (7.21,15.02,7.41,15.22), (7.21,15.02,7.41,15.22), (9.36,15.02,9.56,15.22), (9.36,15.02,9.56,15.22), (9.36,15.02,9.56,15.22), (9.36,15.02,9.56,15.22)])
R(cp_0, met3, [(7.145,3.38,7.475,4.18), (7.145,3.38,7.475,4.18), (7.145,3.38,7.475,4.18), (7.145,3.38,7.475,4.18), (7.31,3.38,9.46,4.18), (9.295,3.38,9.625,4.18), (9.295,3.38,9.625,4.18), (9.295,3.38,9.625,4.18), (9.295,3.38,9.625,4.18), (1.125,14.72,1.455,15.52), (1.125,14.72,1.455,15.52), (1.29,14.72,2.15,15.52), (1.985,14.72,2.315,15.52), (1.985,14.72,2.315,15.52), (7.145,14.72,7.475,15.52), (7.145,14.72,7.475,15.52), (7.145,14.72,7.475,15.52), (7.145,14.72,7.475,15.52), (7.31,14.72,9.46,15.52), (9.295,14.72,9.625,15.52), (9.295,14.72,9.625,15.52), (9.295,14.72,9.625,15.52), (9.295,14.72,9.625,15.52)])
R(cp_0, L104_0, [(-4,-4,15.18,26.68)])
R(cp_0, L235_5, [(0,0,11.18,22.68)])
cp_0.add(gdstk.Reference(scm_nmos_16357927_x1_y1_, (5.16,15.12)))
cp_0.add(gdstk.Reference(scm_pmos_15963850_x1_y1_, (5.16,7.56), x_reflection=True))
cp_0.add(gdstk.Reference(inv_92586643_0_0_1670320, (2.58,15.12), rotation=pi))
cp_0.add(gdstk.Reference(inv_92586643_1_0_1670320, (8.6,15.12), x_reflection=True))
cp_0.add(gdstk.Reference(dcl_nmos_s_62101695_x1_y, (11.18,15.12), rotation=pi, x_reflection=True))
cp_0.add(gdstk.Reference(dcl_pmos_s_57934405_x1_y, (2.58,7.56), x_reflection=True))
cp_0.add(gdstk.Reference(nmos_s_58782418_x1_y1_16, (2.58,15.12)))
cp_0.add(gdstk.Reference(c_nmos_s_96839798_x1_y1_16_, (0,15.12)))
cp_0.add(gdstk.Reference(pmos_s_48783884_x1_y1_16, (3.44,15.12), x_reflection=True))
cp_0.add(gdstk.Reference(pmos_s_63670781_x1_y1_16, (8.6,15.12), rotation=pi))
cp_0.add(gdstk.Label('VSS', (7.31,19.11), layer=69, texttype=5))
cp_0.add(gdstk.Label('VDD', (7.31,3.57), layer=69, texttype=5))
cp_0.add(gdstk.Label('UP', (0.86,7.98), layer=68, texttype=5))
cp_0.add(gdstk.Label('DN', (10.32,7.98), layer=68, texttype=5))
cp_0.add(gdstk.Label('OUT', (0.86,15.54), layer=68, texttype=5))

lib.write_gds('CP_0.gds')
